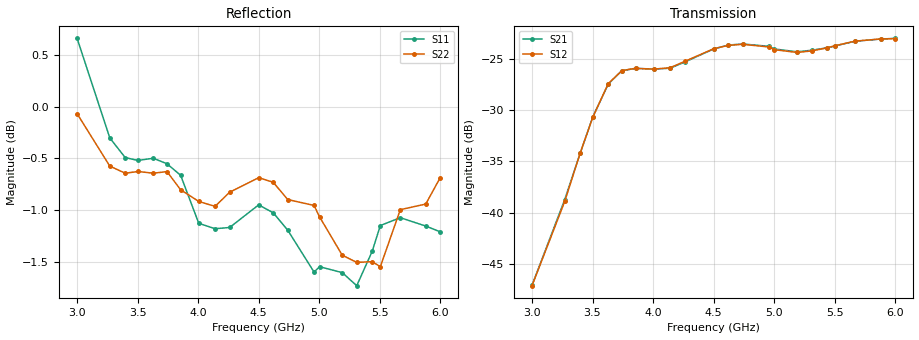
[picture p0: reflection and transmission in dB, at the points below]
!  26/11/2025  15:47:14
! Ref Plane: 0.000 mm
# MHZ S MA R  50
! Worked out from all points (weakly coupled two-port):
!   401 points, 3 GHz to 6 GHz, reference 50 ohm
!   highest |S21| = -22.99 dB at 6 GHz (marker M1); lowest = -47.1 dB at 3 GHz (marker M2)
!   lowest |S11| = -1.7 dB at 5.31 GHz (marker M3), VSWR 10.08, Z = 4.97 + j2.12 ohm
!   |S11| at or under -10 dB: nowhere
!   |S22| runs from -1.5 to 0.0 dB; largest |S21 - S12| = 0.0029
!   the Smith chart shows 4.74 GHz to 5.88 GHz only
!   S11 on the Smith chart (normalised r, x): 4.74 GHz: 2.49, -5.41; 4.957 GHz: 0.19, -1.05; 5.19 GHz: 0.10, -0.23; 5.438 GHz: 0.09, +0.39; 5.67 GHz: 0.17, +1.33; 5.88 GHz: 5.61, +7.25
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3000  1.079 -138.6  0.004425 49.7  0.004405 52.4  0.9923 -106.2
3270  0.9659 151.3  0.01158 -17.1  0.01134 -14.1  0.9361 -170.9
3397.5  0.945 108.2  0.01947 -56.9  0.0195 -55.8  0.9287 150.6
3502.5  0.942 65.3  0.02934 -97.2  0.02926 -95.9  0.9305 112.8
3630  0.9443 9.9  0.04242 -153.0  0.04264 -151.8  0.9287 58.1
3742.5  0.9385 -40.4  0.04931 156.9  0.04932 158.5  0.9304 10.0
3855  0.9266 -86.1  0.05055 110.8  0.0506 112.3  0.9118 -36.0
4005  0.8784 -140.0  0.05023 57.9  0.05015 59.0  0.9 -88.1
4140  0.8731 174.6  0.05064 15.6  0.05093 17.3  0.8951 -129.2
4260  0.8743 139.2  0.05423 -20.2  0.05465 -18.3  0.9093 -166.8
4500  0.8966 62.4  0.06288 -95.2  0.06306 -93.8  0.9241 119.1
4620  0.8887 22.2  0.06572 -134.3  0.06545 -133.2  0.9194 81.5
4740  0.8717 -17.4  0.06651 -173.8  0.06629 -172.3  0.9019 43.3
4957.5  0.832 -86.4  0.0648 120.1  0.0643 121.5  0.896 -17.8
5002.5  0.837 -100.8  0.06289 106.8  0.06238 108.0  0.8848 -31.8
5190  0.8315 -154.0  0.06091 54.6  0.06048 55.6  0.8478 -85.0
5310  0.8195 175.1  0.062 22.0  0.06152 23.4  0.841 -121.3
5437.5  0.8514 136.9  0.06375 -12.7  0.06366 -10.7  0.8417 -154.2
5505  0.8762 118.9  0.06511 -30.9  0.06528 -28.9  0.837 -173.5
5670  0.8839 73.3  0.06863 -77.1  0.06869 -74.8  0.8918 142.4
5880  0.8757 9.9  0.07031 -139.1  0.07036 -137.1  0.8974 84.2
6000  0.8701 -23.0  0.07085 -171.9  0.07065 -170.3  0.9242 53.4
